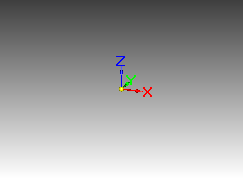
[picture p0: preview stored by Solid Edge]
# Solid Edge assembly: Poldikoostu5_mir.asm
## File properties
Author: Türk
Template: Iso Assembly.asm
Last saved by: Türk
Revision: 2
Application: Solid Edge
Username: Türk
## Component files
Mutter.par
Polt59x20.par
